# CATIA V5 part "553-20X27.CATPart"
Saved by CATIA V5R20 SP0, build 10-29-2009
Part number: 553-20X27
Definition: NONE
Nomenclature: 553-20X27
Source: Unknown
Description: 553-20X27
Bounding box of the stored display mesh (mm): x 0 to 27, y -15.5 to 15.5, z -15.5 to 15.5
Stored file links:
  C:\Users\Utente\Desktop\IO LAVORO\3D X SITO CF\X SITO\PLASTICA\553\553-20X27.CATPart

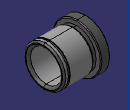
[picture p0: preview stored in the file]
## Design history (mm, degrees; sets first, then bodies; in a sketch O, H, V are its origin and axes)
Body1 "553-20X27" (main body)
  Solid1: solid without history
